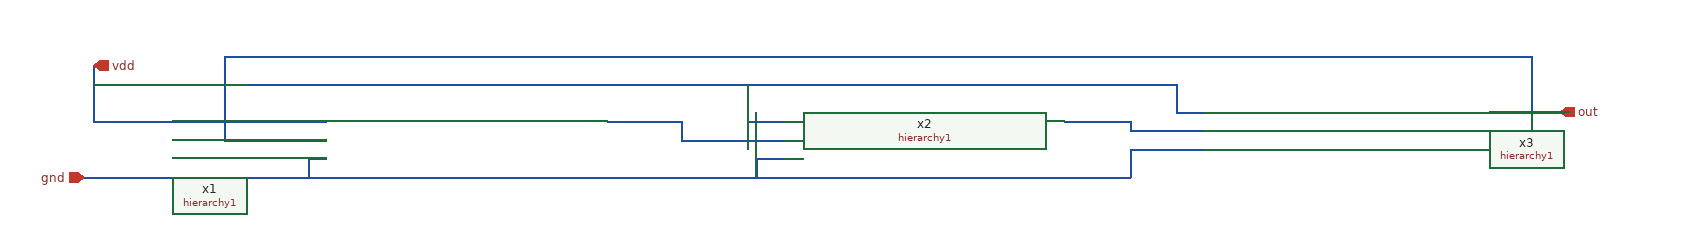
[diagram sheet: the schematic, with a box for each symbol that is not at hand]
v {xschem version=3.4.6RC file_version=1.2
}
G {}
K {}
V {}
S {}
E {}
N -1940 -130 -1940 -70 {lab=vdd}
N -1940 -70 -1690 -70 {lab=vdd}
N -450 -80 -360 -80 {lab=xxx}
N -1310 -70 -1310 -50 {lab=#net1}
N -1310 -50 -1200 -50 {lab=#net1}
N -900 -70 -830 -70 {lab=#net2}
N -830 -70 -830 -60 {lab=#net2}
N -830 -60 -750 -60 {lab=#net2}
N -1800 -50 -1690 -50 {lab=xxx}
N -1800 -140 -1800 -50 {lab=xxx}
N -1800 -140 -400 -140 {lab=xxx}
N -400 -140 -400 -80 {lab=xxx}
N -830 -40 -750 -40 {lab=gnd}
N -830 -40 -830 -10 {lab=gnd}
N -1950 -10 -830 -10 {lab=gnd}
N -1710 -30 -1690 -30 {lab=gnd}
N -1710 -30 -1710 -10 {lab=gnd}
N -1230 -30 -1200 -30 {lab=gnd}
N -1230 -30 -1230 -10 {lab=gnd}
N -780 -80 -750 -80 {lab=vdd}
N -780 -110 -780 -80 {lab=vdd}
N -1940 -110 -780 -110 {lab=vdd}
N -1240 -70 -1200 -70 {lab=vdd}
N -1240 -110 -1240 -70 {lab=vdd}
N -1390 -70 -1310 -70 {lab=#net1}
C {devices/iopin.sym} -1940 -130 0 1 {name=p1 lab=vdd}
C {devices/iopin.sym} -1950 -10 2 0 {name=p2 lab=gnd}
C {devices/opin.sym} -370 -80 0 0 {name=p3 lab=out}
C {/home/fazya09/hierarchy1.sym} -1540 -50 0 0 {name=x1}
C {/home/fazya09/hierarchy1.sym} -1050 -50 0 0 {name=x2}
C {/home/fazya09/hierarchy1.sym} -600 -60 0 0 {name=x3}
